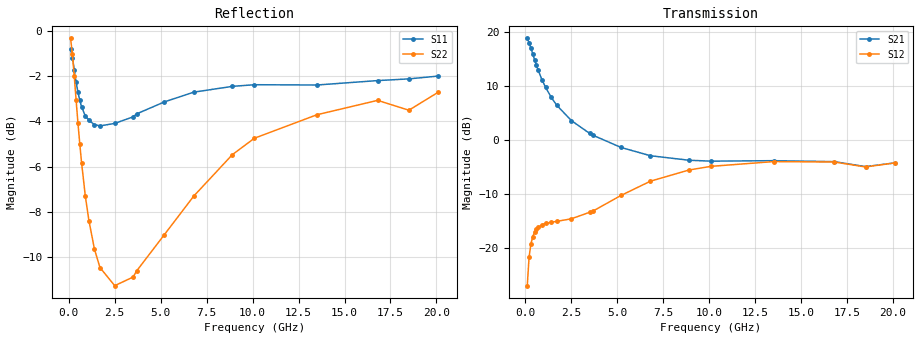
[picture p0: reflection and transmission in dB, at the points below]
!  Infineon Technologies AG
! BFR380L3 , PF131585-7, No.6, Th 09.10.01, soldered on pcb-board, measured with PP GSG850
!  Vce=0.5 V,  Ic=2.5 mA
! Common Emitter S-Parameters:  15. November 2001
#  GHz  S  MA  R  50
! f  S11  S21  S12  S22
! GHz  Mag  Ang  Mag  Ang  Mag  Ang  Mag  Ang
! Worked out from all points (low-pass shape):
!   201 points, 100 MHz to 20.1 GHz, reference 50 ohm
!   highest |S21| = 18.81 dB at 100 MHz (marker M1); lowest = -5.0 dB at 18.5 GHz (marker M2)
!   |S21| within 3 dB of the highest: start of sweep to 410.4 MHz
!   lowest |S11| = -4.2 dB at 1.7 GHz (marker M3), VSWR 4.22, Z = 11.9 - j4.09 ohm
!   |S11| at or under -10 dB: nowhere
!   |S22| runs from -11.3 to -0.3 dB; largest |S21 - S12| = 8.7
!   S11 on the Smith chart (normalised r, x): 100 MHz: 0.97, -4.33; 400 MHz: 0.29, -1.08; 1.1 GHz: 0.24, -0.29; 3.7 GHz: 0.23, +0.29; 8.9 GHz: 0.30, +1.05; 20.1 GHz: 0.95, +2.55
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0.1  0.9104 -24.9  8.724 163.6  0.04439 75.9  0.9635 -15.6
0.2  0.8739 -47.2  7.929 149.0  0.08134 63.8  0.8878 -29.5
0.3  0.8208 -67.0  7.087 136.8  0.1085 54.0  0.7939 -40.8
0.4  0.7704 -83.4  6.255 126.7  0.1268 46.5  0.7044 -49.9
0.5  0.7334 -97.3  5.53 118.4  0.1397 41.0  0.6269 -57.2
0.6  0.7022 -108.6  4.906 111.7  0.1489 36.9  0.5631 -63.1
0.7  0.6795 -118.4  4.396 105.8  0.1551 33.7  0.5107 -68.1
0.9  0.6494 -133.9  3.608 96.5  0.1629 29.5  0.4319 -76.0
1.1  0.6349 -145.8  3.061 88.9  0.168 26.9  0.3803 -82.3
1.4  0.6208 -159.4  2.484 79.6  0.1719 25.5  0.3291 -90.2
1.7  0.6169 -170.1  2.097 71.7  0.1752 25.4  0.2998 -97.1
2.5  0.6248 168.9  1.507 54.8  0.1852 28.9  0.2734 -113.3
3.5  0.646 149.2  1.145 38.4  0.213 35.8  0.2857 -132.6
3.7  0.6561 146.3  1.097 35.7  0.2197 36.5  0.295 -136.8
5.2  0.6971 123.9  0.8501 18.9  0.3048 38.6  0.3545 -163.7
6.8  0.7326 103.9  0.7118 8.3  0.4134 32.3  0.4315 168.5
8.9  0.7545 84.7  0.6465 -0.1  0.525 18.3  0.5329 140.7
10.1  0.7609 75.8  0.634 -4.6  0.5675 9.7  0.5794 126.3
13.5  0.7598 58.5  0.6406 -18.6  0.6281 -12.0  0.653 95.4
16.8  0.7771 47.0  0.6273 -30.7  0.6226 -27.5  0.7026 74.3
18.5  0.7838 45.2  0.5642 -38.3  0.5602 -35.7  0.6682 69.1
20.1  0.7952 38.5  0.6111 -42.2  0.6113 -40.4  0.7325 58.7
